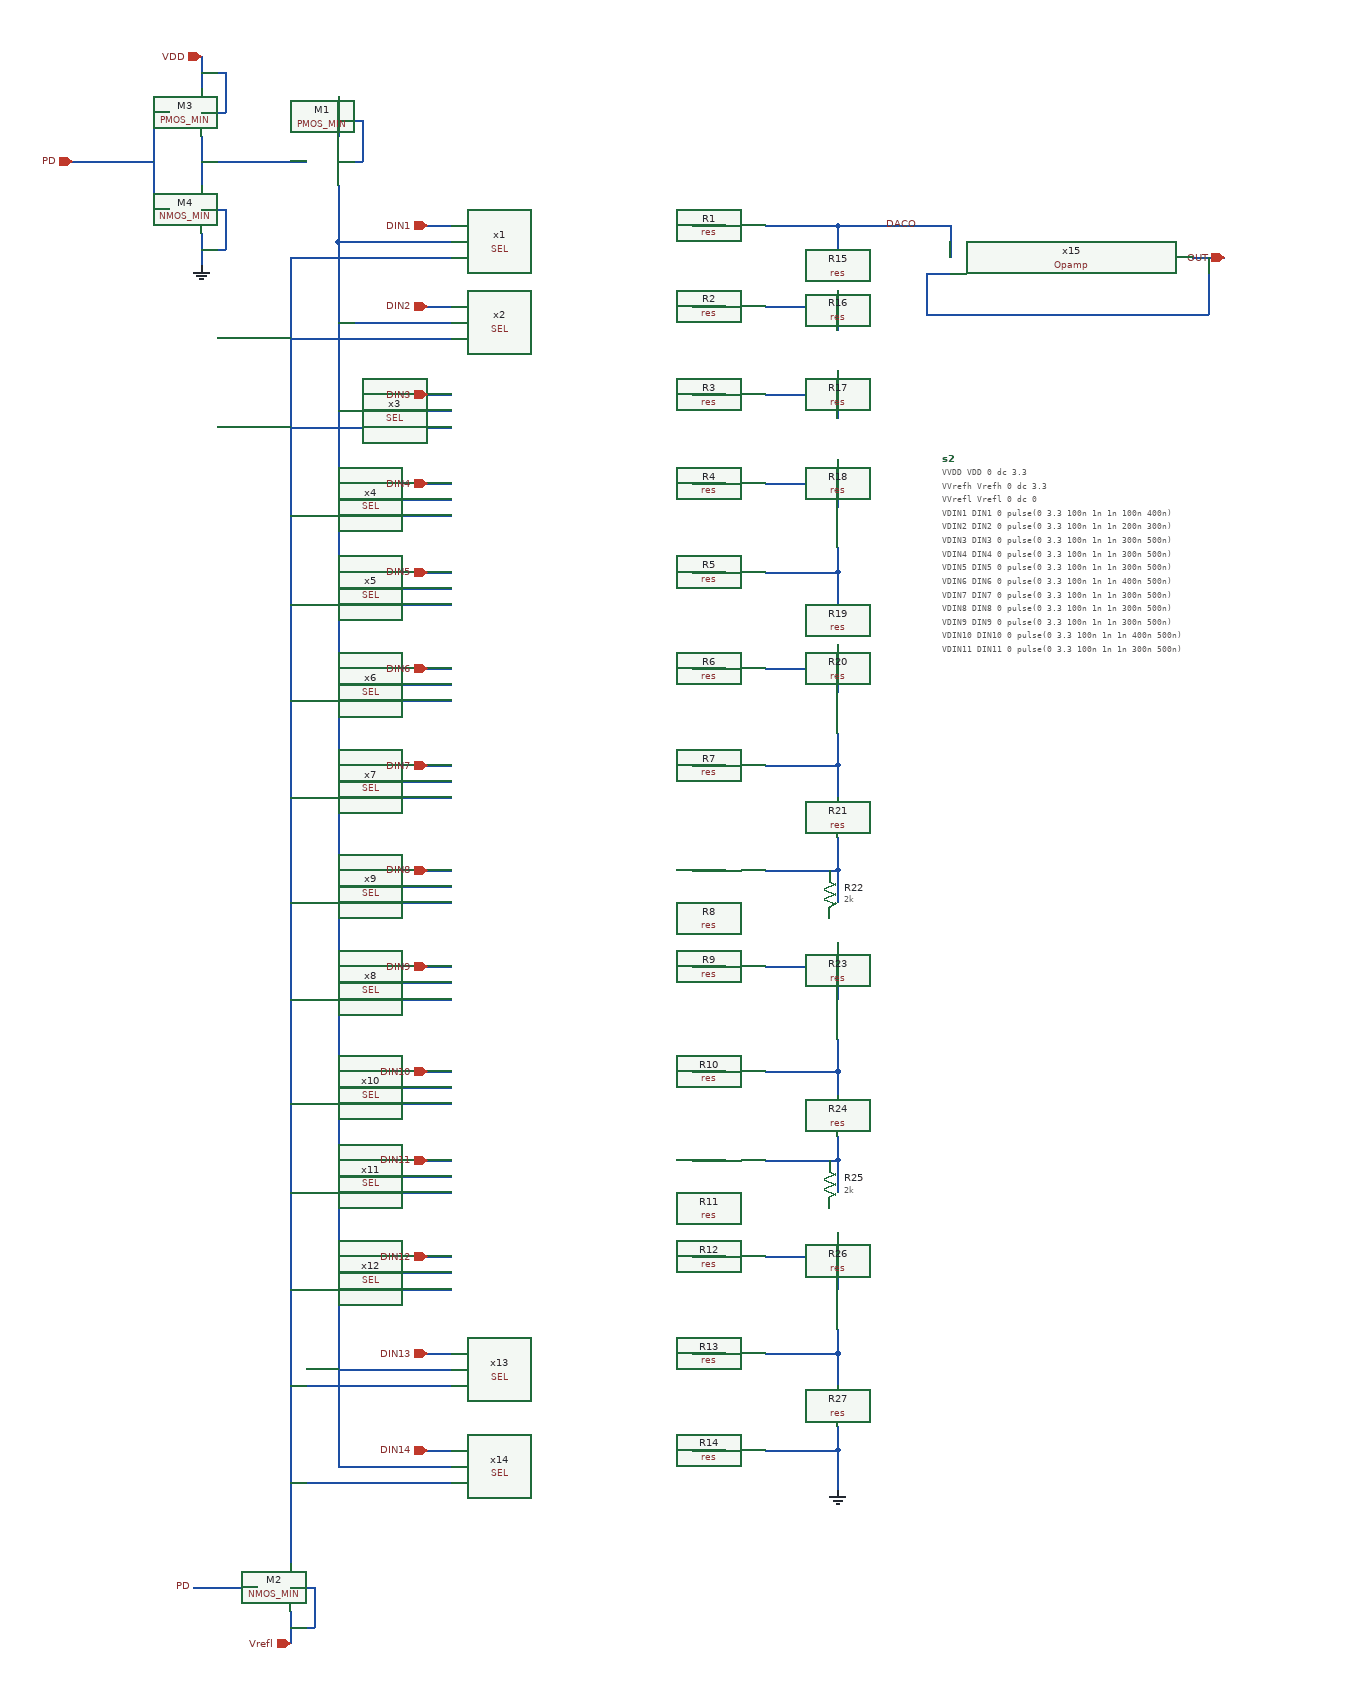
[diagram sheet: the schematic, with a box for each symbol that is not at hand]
v {xschem version=3.4.8RC file_version=1.3}
G {}
K {}
V {}
S {}
F {}
E {}
N 50 -100 140 -100 {lab=DACO}
N 50 0 140 0 {lab=#net1}
N -40 -100 -0 -100 {lab=#net2}
N -40 -0 0 0 {lab=#net3}
N -40 110 -0 110 {lab=#net4}
N -40 220 -0 220 {lab=#net5}
N -40 330 -0 330 {lab=#net6}
N -40 450 -0 450 {lab=#net7}
N -40 570 -0 570 {lab=#net8}
N -40 700 0 700 {lab=#net9}
N -40 820 -0 820 {lab=#net10}
N -40 950 -0 950 {lab=#net11}
N -40 1060 -0 1060 {lab=#net12}
N -40 1180 -0 1180 {lab=#net13}
N -40 1300 -0 1300 {lab=#net14}
N -40 1420 -0 1420 {lab=#net15}
N -480 -80 -340 -80 {lab=#net16}
N -480 -80 -480 1440 {lab=#net16}
N -480 1440 -340 1440 {lab=#net16}
N -480 1320 -340 1320 {lab=#net16}
N -480 1200 -340 1200 {lab=#net16}
N -480 1080 -340 1080 {lab=#net16}
N -480 970 -340 970 {lab=#net16}
N -480 840 -340 840 {lab=#net16}
N -480 720 -340 720 {lab=#net16}
N -480 590 -340 590 {lab=#net16}
N -480 470 -340 470 {lab=#net16}
N -480 350 -340 350 {lab=#net16}
N -480 240 -340 240 {lab=#net16}
N -480 130 -340 130 {lab=#net16}
N -480 20 -340 20 {lab=#net16}
N -540 -60 -340 -60 {lab=#net17}
N -540 -60 -540 1530 {lab=#net17}
N -540 1460 -340 1460 {lab=#net17}
N -540 1340 -340 1340 {lab=#net17}
N -540 1220 -340 1220 {lab=#net17}
N -540 1100 -340 1100 {lab=#net17}
N -540 990 -340 990 {lab=#net17}
N -540 860 -340 860 {lab=#net17}
N -540 740 -340 740 {lab=#net17}
N -540 610 -340 610 {lab=#net17}
N -540 490 -340 490 {lab=#net17}
N -540 370 -340 370 {lab=#net17}
N -540 260 -340 260 {lab=#net17}
N -540 150 -340 150 {lab=#net17}
N -540 40 -340 40 {lab=#net17}
N 580 -60 620 -60 {lab=OUT}
N 140 -100 280 -100 {lab=DACO}
N -370 -100 -340 -100 {lab=DIN1}
N -370 0 -340 0 {lab=DIN2}
N -370 110 -340 110 {lab=DIN3}
N -370 220 -340 220 {lab=DIN4}
N -370 330 -340 330 {lab=DIN5}
N -370 450 -340 450 {lab=DIN6}
N -370 570 -340 570 {lab=DIN7}
N -370 700 -340 700 {lab=DIN8}
N -370 820 -340 820 {lab=DIN9}
N -370 950 -340 950 {lab=DIN10}
N -370 1060 -340 1060 {lab=DIN11}
N -370 1180 -340 1180 {lab=DIN12}
N -370 1300 -340 1300 {lab=DIN13}
N -370 1420 -340 1420 {lab=DIN14}
N 280 -100 280 -60 {lab=DACO}
N 600 -60 600 10 {lab=OUT}
N 250 10 600 10 {lab=OUT}
N 250 -40 250 10 {lab=OUT}
N 250 -40 280 -40 {lab=OUT}
N 140 -100 140 -70 {lab=DACO}
N 140 -20 140 -0 {lab=#net1}
N 50 110 140 110 {lab=#net18}
N 140 90 140 110 {lab=#net18}
N 140 0 140 30 {lab=#net1}
N 140 80 140 90 {lab=#net18}
N 50 220 140 220 {lab=#net19}
N 140 110 140 140 {lab=#net18}
N 140 190 140 220 {lab=#net19}
N 50 330 140 330 {lab=#net20}
N 140 220 140 250 {lab=#net19}
N 140 300 140 330 {lab=#net20}
N 50 450 140 450 {lab=#net21}
N 50 570 140 570 {lab=#net22}
N 50 700 130 700 {lab=#net23}
N 130 700 140 700 {lab=#net23}
N 140 330 140 370 {lab=#net20}
N 140 420 140 450 {lab=#net21}
N 140 450 140 480 {lab=#net21}
N 140 530 140 570 {lab=#net22}
N 140 570 140 610 {lab=#net22}
N 140 660 140 700 {lab=#net23}
N 140 700 140 740 {lab=#net23}
N 50 820 140 820 {lab=#net24}
N 140 790 140 820 {lab=#net24}
N 50 950 130 950 {lab=#net25}
N 50 1060 130 1060 {lab=#net26}
N 130 950 140 950 {lab=#net25}
N 130 1060 140 1060 {lab=#net26}
N 50 1180 140 1180 {lab=#net27}
N 140 820 140 860 {lab=#net24}
N 140 910 140 950 {lab=#net25}
N 140 950 140 980 {lab=#net25}
N 140 1030 140 1060 {lab=#net26}
N 140 1060 140 1100 {lab=#net26}
N 140 1150 140 1180 {lab=#net27}
N 50 1300 140 1300 {lab=#net28}
N 50 1420 140 1420 {lab=GND}
N 140 1180 140 1220 {lab=#net27}
N 140 1270 140 1300 {lab=#net28}
N 140 1300 140 1340 {lab=#net28}
N 140 1390 140 1420 {lab=GND}
N 140 1420 140 1470 {lab=GND}
N -480 -260 -480 -210 {lab=Vrefh}
N -480 -150 -480 -80 {lab=#net16}
N -540 1530 -540 1560 {lab=#net17}
N -540 1620 -540 1660 {lab=Vrefl}
N -540 1590 -510 1590 {lab=Vrefl}
N -510 1590 -510 1640 {lab=Vrefl}
N -540 1640 -510 1640 {lab=Vrefl}
N -480 -180 -450 -180 {lab=Vrefh}
N -480 -230 -450 -230 {lab=Vrefh}
N -450 -230 -450 -180 {lab=Vrefh}
N -610 -180 -520 -180 {lab=#net29}
N -650 -90 -650 -50 {lab=GND}
N -650 -120 -620 -120 {lab=GND}
N -620 -120 -620 -70 {lab=GND}
N -650 -70 -620 -70 {lab=GND}
N -650 -210 -650 -150 {lab=#net29}
N -650 -180 -610 -180 {lab=#net29}
N -710 -240 -690 -240 {lab=PD}
N -710 -240 -710 -120 {lab=PD}
N -710 -120 -690 -120 {lab=PD}
N -810 -180 -710 -180 {lab=PD}
N -650 -310 -650 -270 {lab=VDD}
N -650 -290 -620 -290 {lab=VDD}
N -620 -290 -620 -240 {lab=VDD}
N -650 -240 -620 -240 {lab=VDD}
N -660 1590 -580 1590 {lab=PD}
C {res.sym} 60 -110 1 0 {name=R1
value=4k
footprint=1206
device=resistor
m=1}
C {res.sym} 130 -80 0 0 {name=R15
value=2k
footprint=1206
device=resistor
m=1}
C {/home/raidonn/LRCircuit/work2/SEL.sym} -190 -80 0 0 {name=x1}
C {/home/raidonn/LRCircuit/work2/SEL.sym} -190 20 0 0 {name=x2}
C {/home/raidonn/LRCircuit/work2/SEL.sym} -190 130 0 0 {name=x3}
C {/home/raidonn/LRCircuit/work2/SEL.sym} -190 240 0 0 {name=x4}
C {/home/raidonn/LRCircuit/work2/SEL.sym} -190 350 0 0 {name=x5}
C {/home/raidonn/LRCircuit/work2/SEL.sym} -190 470 0 0 {name=x6}
C {/home/raidonn/LRCircuit/work2/SEL.sym} -190 590 0 0 {name=x7}
C {/home/raidonn/LRCircuit/work2/SEL.sym} -190 840 0 0 {name=x8}
C {/home/raidonn/LRCircuit/work2/SEL.sym} -190 720 0 0 {name=x9}
C {/home/raidonn/LRCircuit/work2/SEL.sym} -190 970 0 0 {name=x10}
C {/home/raidonn/LRCircuit/work2/SEL.sym} -190 1080 0 0 {name=x11}
C {/home/raidonn/LRCircuit/work2/SEL.sym} -190 1200 0 0 {name=x12}
C {/home/raidonn/LRCircuit/work2/SEL.sym} -190 1320 0 0 {name=x13}
C {/home/raidonn/LRCircuit/work2/SEL.sym} -190 1440 0 0 {name=x14}
C {ipin.sym} -480 -250 1 0 {name=p1 lab=Vrefh}
C {ipin.sym} -540 1660 3 0 {name=p2 lab=Vrefl}
C {iopin.sym} 620 -60 0 0 {name=p3 lab=OUT}
C {ipin.sym} -370 -100 0 0 {name=p4 lab=DIN1}
C {ipin.sym} -370 0 0 0 {name=p6 lab=DIN2}
C {ipin.sym} -370 110 0 0 {name=p7 lab=DIN3}
C {ipin.sym} -370 220 0 0 {name=p8 lab=DIN4}
C {ipin.sym} -370 330 0 0 {name=p9 lab=DIN5}
C {ipin.sym} -370 450 0 0 {name=p10 lab=DIN6}
C {ipin.sym} -370 570 0 0 {name=p11 lab=DIN7}
C {ipin.sym} -370 700 0 0 {name=p12 lab=DIN8}
C {ipin.sym} -370 820 0 0 {name=p13 lab=DIN9}
C {ipin.sym} -370 950 0 0 {name=p14 lab=DIN10}
C {ipin.sym} -370 1060 0 0 {name=p15 lab=DIN11}
C {ipin.sym} -370 1180 0 0 {name=p16 lab=DIN12}
C {ipin.sym} -370 1300 0 0 {name=p17 lab=DIN13}
C {ipin.sym} -370 1420 0 0 {name=p18 lab=DIN14}
C {code_shown.sym} 270 190 0 0 {name=s2 only_toplevel=false value=
"
VVDD VDD 0 dc 3.3
VVrefh Vrefh 0 dc 3.3
VVrefl Vrefl 0 dc 0

VDIN1 DIN1 0 pulse(0 3.3 100n 1n 1n 100n 400n)
VDIN2 DIN2 0 pulse(0 3.3 100n 1n 1n 200n 300n)
VDIN3 DIN3 0 pulse(0 3.3 100n 1n 1n 300n 500n)
VDIN4 DIN4 0 pulse(0 3.3 100n 1n 1n 300n 500n)
VDIN5 DIN5 0 pulse(0 3.3 100n 1n 1n 300n 500n)
VDIN6 DIN6 0 pulse(0 3.3 100n 1n 1n 400n 500n)
VDIN7 DIN7 0 pulse(0 3.3 100n 1n 1n 300n 500n)
VDIN8 DIN8 0 pulse(0 3.3 100n 1n 1n 300n 500n)
VDIN9 DIN9 0 pulse(0 3.3 100n 1n 1n 300n 500n)
VDIN10 DIN10 0 pulse(0 3.3 100n 1n 1n 400n 500n)
VDIN11 DIN11 0 pulse(0 3.3 100n 1n 1n 300n 500n)
VDIN12 DIN12 0 pulse(0 3.3 100n 1n 1n 300n 500n)
VDIN13 DIN13 0 pulse(0 3.3 100n 1n 1n 300n 500n)
VDIN14 DIN14 0 pulse(0 3.3 100n 1n 1n 400n 500n)

.include /home/raidonn/LRCircuit/spicemodel/ocs65_stl_n3_typ.para
.include /home/raidonn/LRCircuit/spicemodel/ocs65_stl_p3_typ.para

.control
save all
tran 1n 500n
plot V(DACO) 
*plot V(OUT)

write "RDAC_ver2.raw"

.endc"
}
C {/home/raidonn/LRCircuit/work2/Opamp.sym} 430 -50 0 0 {name=x15}
C {res.sym} 60 -10 1 0 {name=R2
value=4k
footprint=1206
device=resistor
m=1}
C {res.sym} 60 100 1 0 {name=R3
value=4k
footprint=1206
device=resistor
m=1}
C {res.sym} 60 210 1 0 {name=R4
value=4k
footprint=1206
device=resistor
m=1}
C {res.sym} 60 320 1 0 {name=R5
value=4k
footprint=1206
device=resistor
m=1}
C {res.sym} 60 440 1 0 {name=R6
value=4k
footprint=1206
device=resistor
m=1}
C {res.sym} 60 560 1 0 {name=R7
value=4k
footprint=1206
device=resistor
m=1}
C {res.sym} 60 690 1 0 {name=R8
value=4k
footprint=1206
device=resistor
m=1}
C {res.sym} 60 810 1 0 {name=R9
value=4k
footprint=1206
device=resistor
m=1}
C {res.sym} 60 940 1 0 {name=R10
value=4k
footprint=1206
device=resistor
m=1}
C {res.sym} 60 1050 1 0 {name=R11
value=4k
footprint=1206
device=resistor
m=1}
C {res.sym} 60 1170 1 0 {name=R12
value=4k
footprint=1206
device=resistor
m=1}
C {res.sym} 60 1290 1 0 {name=R13
value=4k
footprint=1206
device=resistor
m=1}
C {res.sym} 60 1410 1 0 {name=R14
value=4k
footprint=1206
device=resistor
m=1}
C {res.sym} 130 20 0 0 {name=R16
value=2k
footprint=1206
device=resistor
m=1}
C {res.sym} 130 130 0 0 {name=R17
value=2k
footprint=1206
device=resistor
m=1}
C {res.sym} 130 240 0 0 {name=R18
value=2k
footprint=1206
device=resistor
m=1}
C {res.sym} 130 360 0 0 {name=R19
value=2k
footprint=1206
device=resistor
m=1}
C {res.sym} 130 470 0 0 {name=R20
value=2k
footprint=1206
device=resistor
m=1}
C {res.sym} 130 600 0 0 {name=R21
value=2k
footprint=1206
device=resistor
m=1}
C {res.sym} 130 730 0 0 {name=R22
value=2k
footprint=1206
device=resistor
m=1}
C {res.sym} 130 850 0 0 {name=R23
value=2k
footprint=1206
device=resistor
m=1}
C {res.sym} 130 970 0 0 {name=R24
value=2k
footprint=1206
device=resistor
m=1}
C {res.sym} 130 1090 0 0 {name=R25
value=2k
footprint=1206
device=resistor
m=1}
C {res.sym} 130 1210 0 0 {name=R26
value=2k
footprint=1206
device=resistor
m=1}
C {res.sym} 130 1330 0 0 {name=R27
value=2k
footprint=1206
device=resistor
m=1}
C {gnd.sym} 140 1470 0 0 {name=l1 lab=GND}
C {PMOS_MIN.sym} -520 -180 0 0 {name=M1 model=p3.0 w=5u l=0.18u as=0 ps=0 ad=0 pd=0 m=1}
C {NMOS_MIN.sym} -580 1590 0 0 {name=M2 model=n3.0 w=5u l=0.18u as=0 ps=0 ad=0 pd=0 m=1}
C {PMOS_MIN.sym} -690 -240 0 0 {name=M3 model=p3.0 w=5u l=0.18u as=0 ps=0 ad=0 pd=0 m=1}
C {NMOS_MIN.sym} -690 -120 0 0 {name=M4 model=n3.0 w=5u l=0.18u as=0 ps=0 ad=0 pd=0 m=1}
C {ipin.sym} -810 -180 0 0 {name=p5 lab=PD}
C {gnd.sym} -650 -50 0 0 {name=l2 lab=GND}
C {ipin.sym} -650 -310 1 0 {name=p19 lab=VDD}
C {lab_pin.sym} -660 1590 0 0 {name=l3 sig_type=std_logic lab=PD}
C {lab_pin.sym} 240 -100 1 0 {name=l4 sig_type=std_logic lab=DACO}
